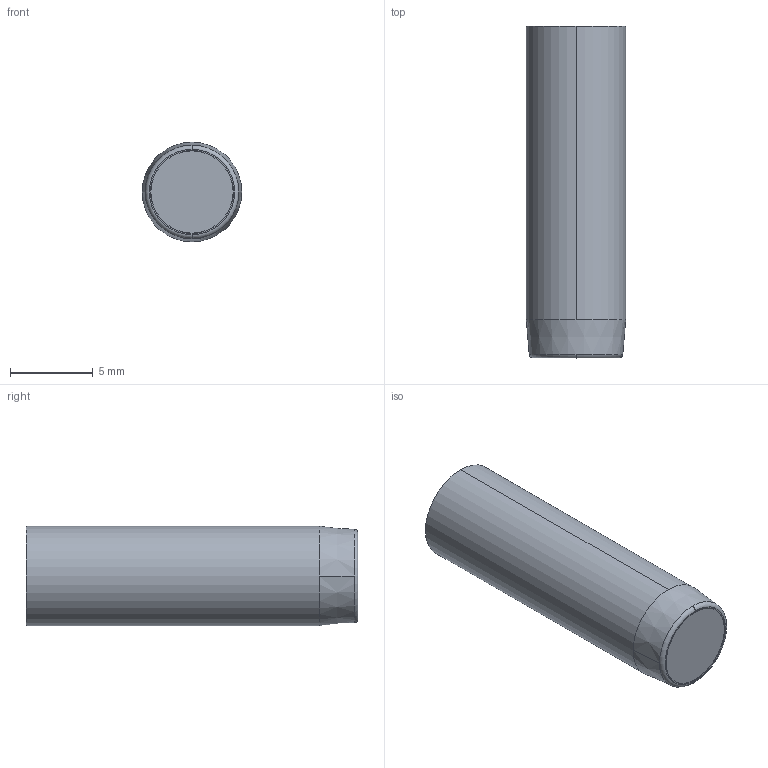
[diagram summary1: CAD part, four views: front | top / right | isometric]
STEP (ISO 10303-21) file: header records copied from the file, then geometry measured from it (millimetres).
FILE_DESCRIPTION (( 'STEP AP214' ), '1' );
FILE_NAME ('FA 063212-20.STEP', '2013-10-01T09:02:21', ( '' ), ( '' ), 'SwSTEP 2.0', 'SolidWorks 2011', '' );
FILE_SCHEMA (( 'AUTOMOTIVE_DESIGN' ));
Length unit declared in the file: millimetre
Products named in the file (6): FA 063212-20; 9FA 063212; FA 063200-1; IA 321720; FA 063200-3; FA 063200-2 - comprimido
Assembly tree (5 placements, depth 2):
  FA 063212-20
    9FA 063212
    FA 063200-3
    FA 063200-2 - comprimido
    IA 321720
    FA 063200-1
Bounding box: 6 x 20 x 6 mm (x, y, z)
Volume: 469.9 mm3; surface area: 1126.9 mm2
Topology: 5 solids, 5 shells, 327 faces, 833 edges, 545 vertices
Faces by surface type: plane 152, cylinder 141, cone 22, torus 10, bspline 2
Entity records: 12003 total; most frequent: CARTESIAN_POINT 3557, DIRECTION 1791, ORIENTED_EDGE 1662, EDGE_CURVE 831, AXIS2_PLACEMENT_3D 663, VERTEX_POINT 545, VECTOR 465, LINE 465
One B-rep face of a CAD part: STEP entity #6787.
In plain terms, the planar face has unit normal (0, -1, 0).
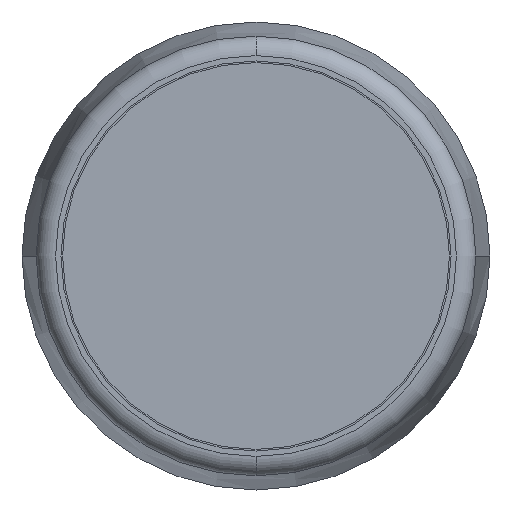
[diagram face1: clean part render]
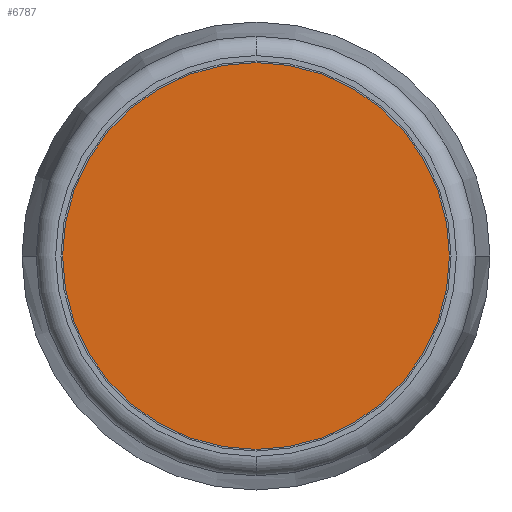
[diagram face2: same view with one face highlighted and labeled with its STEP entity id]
Its self-contained STEP definition (entity closure, numbers rounded to 3 decimals):
#149 = AXIS2_PLACEMENT_3D ( 'NONE', #4289, #4292, #4293 ) ;
#180 = CIRCLE ( 'NONE', #204, 2.5 ) ;
#201 = CIRCLE ( 'NONE', #149, 2.5 ) ;
#204 = AXIS2_PLACEMENT_3D ( 'NONE', #4386, #4384, #4385 ) ;
#664 = VERTEX_POINT ( 'NONE', #2604 ) ;
#738 = VERTEX_POINT ( 'NONE', #1974 ) ;
#797 = AXIS2_PLACEMENT_3D ( 'NONE', #3025, #3021, #3067 ) ;
#1974 = CARTESIAN_POINT ( 'NONE',  ( 0., 0.15, -2.5 ) ) ;
#2604 = CARTESIAN_POINT ( 'NONE',  ( 0., 0.15, 2.5 ) ) ;
#3021 = DIRECTION ( 'NONE',  ( 0., 1., 0. ) ) ;
#3024 = PLANE ( 'NONE',  #797 ) ;
#3025 = CARTESIAN_POINT ( 'NONE',  ( -2.562, 0.15, -10. ) ) ;
#3067 = DIRECTION ( 'NONE',  ( 0., 0., 1. ) ) ;
#3068 = FACE_OUTER_BOUND ( 'NONE', #7927, .T. ) ;
#4289 = CARTESIAN_POINT ( 'NONE',  ( 0., 0.15, 0. ) ) ;
#4292 = DIRECTION ( 'NONE',  ( 0., 1., 0. ) ) ;
#4293 = DIRECTION ( 'NONE',  ( 0., 0., 1. ) ) ;
#4384 = DIRECTION ( 'NONE',  ( 0., 1., 0. ) ) ;
#4385 = DIRECTION ( 'NONE',  ( 0., 0., 1. ) ) ;
#4386 = CARTESIAN_POINT ( 'NONE',  ( 0., 0.15, 0. ) ) ;
#6787 = ADVANCED_FACE ( 'NONE', ( #3068 ), #3024, .F. ) ;
#7636 = ORIENTED_EDGE ( 'NONE', *, *, #11850, .F. ) ;
#7674 = ORIENTED_EDGE ( 'NONE', *, *, #11870, .F. ) ;
#7927 = EDGE_LOOP ( 'NONE', ( #7674, #7636 ) ) ;
#11850 = EDGE_CURVE ( 'NONE', #738, #664, #201, .T. ) ;
#11870 = EDGE_CURVE ( 'NONE', #664, #738, #180, .T. ) ;
